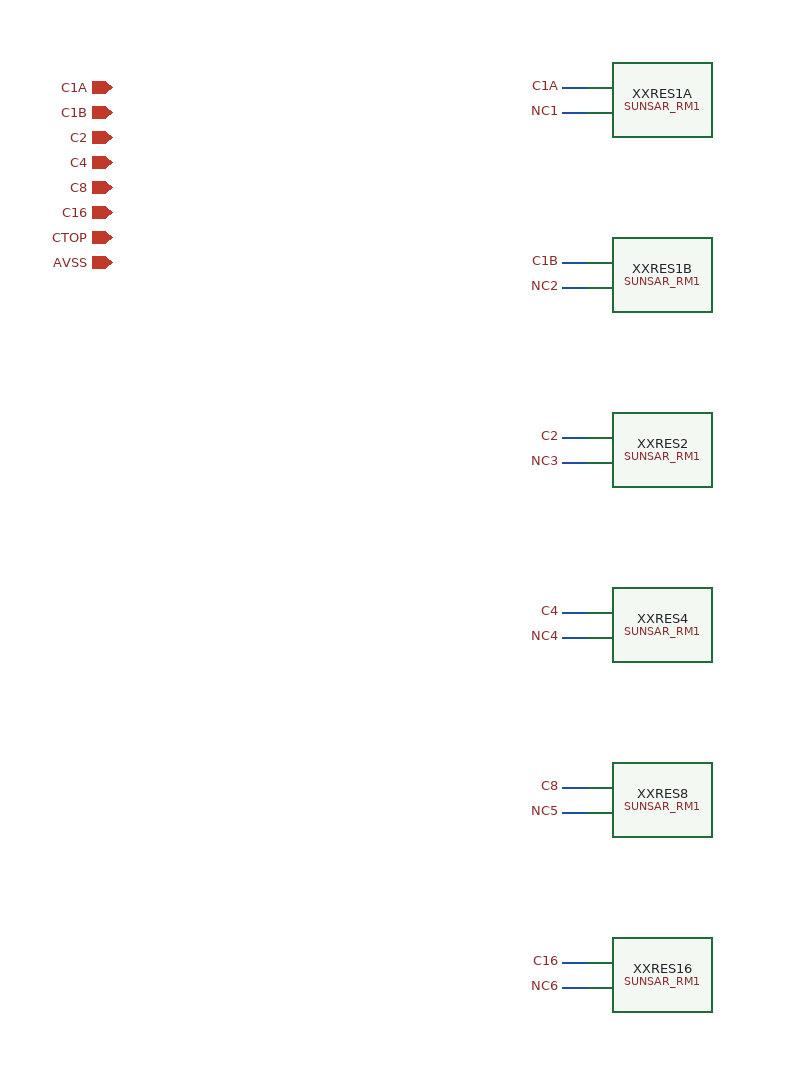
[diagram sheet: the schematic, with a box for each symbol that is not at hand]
v {xschem version=3.0.0 file_version=1.2 }
G {}
K {}
V {}
S {}
E {}
C {devices/iopin.sym} 0 0 0 0{name=p0 lab=C1A}
C {devices/iopin.sym} 0 20 0 0{name=p1 lab=C1B}
C {devices/iopin.sym} 0 40 0 0{name=p2 lab=C2}
C {devices/iopin.sym} 0 60 0 0{name=p3 lab=C4}
C {devices/iopin.sym} 0 80 0 0{name=p4 lab=C8}
C {devices/iopin.sym} 0 100 0 0{name=p5 lab=C16}
C {devices/iopin.sym} 0 120 0 0{name=p6 lab=CTOP}
C {devices/iopin.sym} 0 140 0 0{name=p7 lab=AVSS}
C {SUN_SAR9B_SKY130NM/SUNSAR_RM1.sym} 400 0 0 0 {name=XXRES1A}
N 360.0 0.0 380.0 0.0{lab=C1A}
C {devices/lab_pin.sym} 360.0 0.0 0 0  {name=l0 sig_type=std_logic lab=C1A }
N 360.0 20.0 380.0 20.0{lab=NC1}
C {devices/lab_pin.sym} 360.0 20.0 0 0  {name=l1 sig_type=std_logic lab=NC1 }
C {SUN_SAR9B_SKY130NM/SUNSAR_RM1.sym} 400 140.0 0 0 {name=XXRES1B}
N 360.0 140.0 380.0 140.0{lab=C1B}
C {devices/lab_pin.sym} 360.0 140.0 0 0  {name=l2 sig_type=std_logic lab=C1B }
N 360.0 160.0 380.0 160.0{lab=NC2}
C {devices/lab_pin.sym} 360.0 160.0 0 0  {name=l3 sig_type=std_logic lab=NC2 }
C {SUN_SAR9B_SKY130NM/SUNSAR_RM1.sym} 400 280.0 0 0 {name=XXRES2}
N 360.0 280.0 380.0 280.0{lab=C2}
C {devices/lab_pin.sym} 360.0 280.0 0 0  {name=l4 sig_type=std_logic lab=C2 }
N 360.0 300.0 380.0 300.0{lab=NC3}
C {devices/lab_pin.sym} 360.0 300.0 0 0  {name=l5 sig_type=std_logic lab=NC3 }
C {SUN_SAR9B_SKY130NM/SUNSAR_RM1.sym} 400 420.0 0 0 {name=XXRES4}
N 360.0 420.0 380.0 420.0{lab=C4}
C {devices/lab_pin.sym} 360.0 420.0 0 0  {name=l6 sig_type=std_logic lab=C4 }
N 360.0 440.0 380.0 440.0{lab=NC4}
C {devices/lab_pin.sym} 360.0 440.0 0 0  {name=l7 sig_type=std_logic lab=NC4 }
C {SUN_SAR9B_SKY130NM/SUNSAR_RM1.sym} 400 560.0 0 0 {name=XXRES8}
N 360.0 560.0 380.0 560.0{lab=C8}
C {devices/lab_pin.sym} 360.0 560.0 0 0  {name=l8 sig_type=std_logic lab=C8 }
N 360.0 580.0 380.0 580.0{lab=NC5}
C {devices/lab_pin.sym} 360.0 580.0 0 0  {name=l9 sig_type=std_logic lab=NC5 }
C {SUN_SAR9B_SKY130NM/SUNSAR_RM1.sym} 400 700.0 0 0 {name=XXRES16}
N 360.0 700.0 380.0 700.0{lab=C16}
C {devices/lab_pin.sym} 360.0 700.0 0 0  {name=l10 sig_type=std_logic lab=C16 }
N 360.0 720.0 380.0 720.0{lab=NC6}
C {devices/lab_pin.sym} 360.0 720.0 0 0  {name=l11 sig_type=std_logic lab=NC6 }
